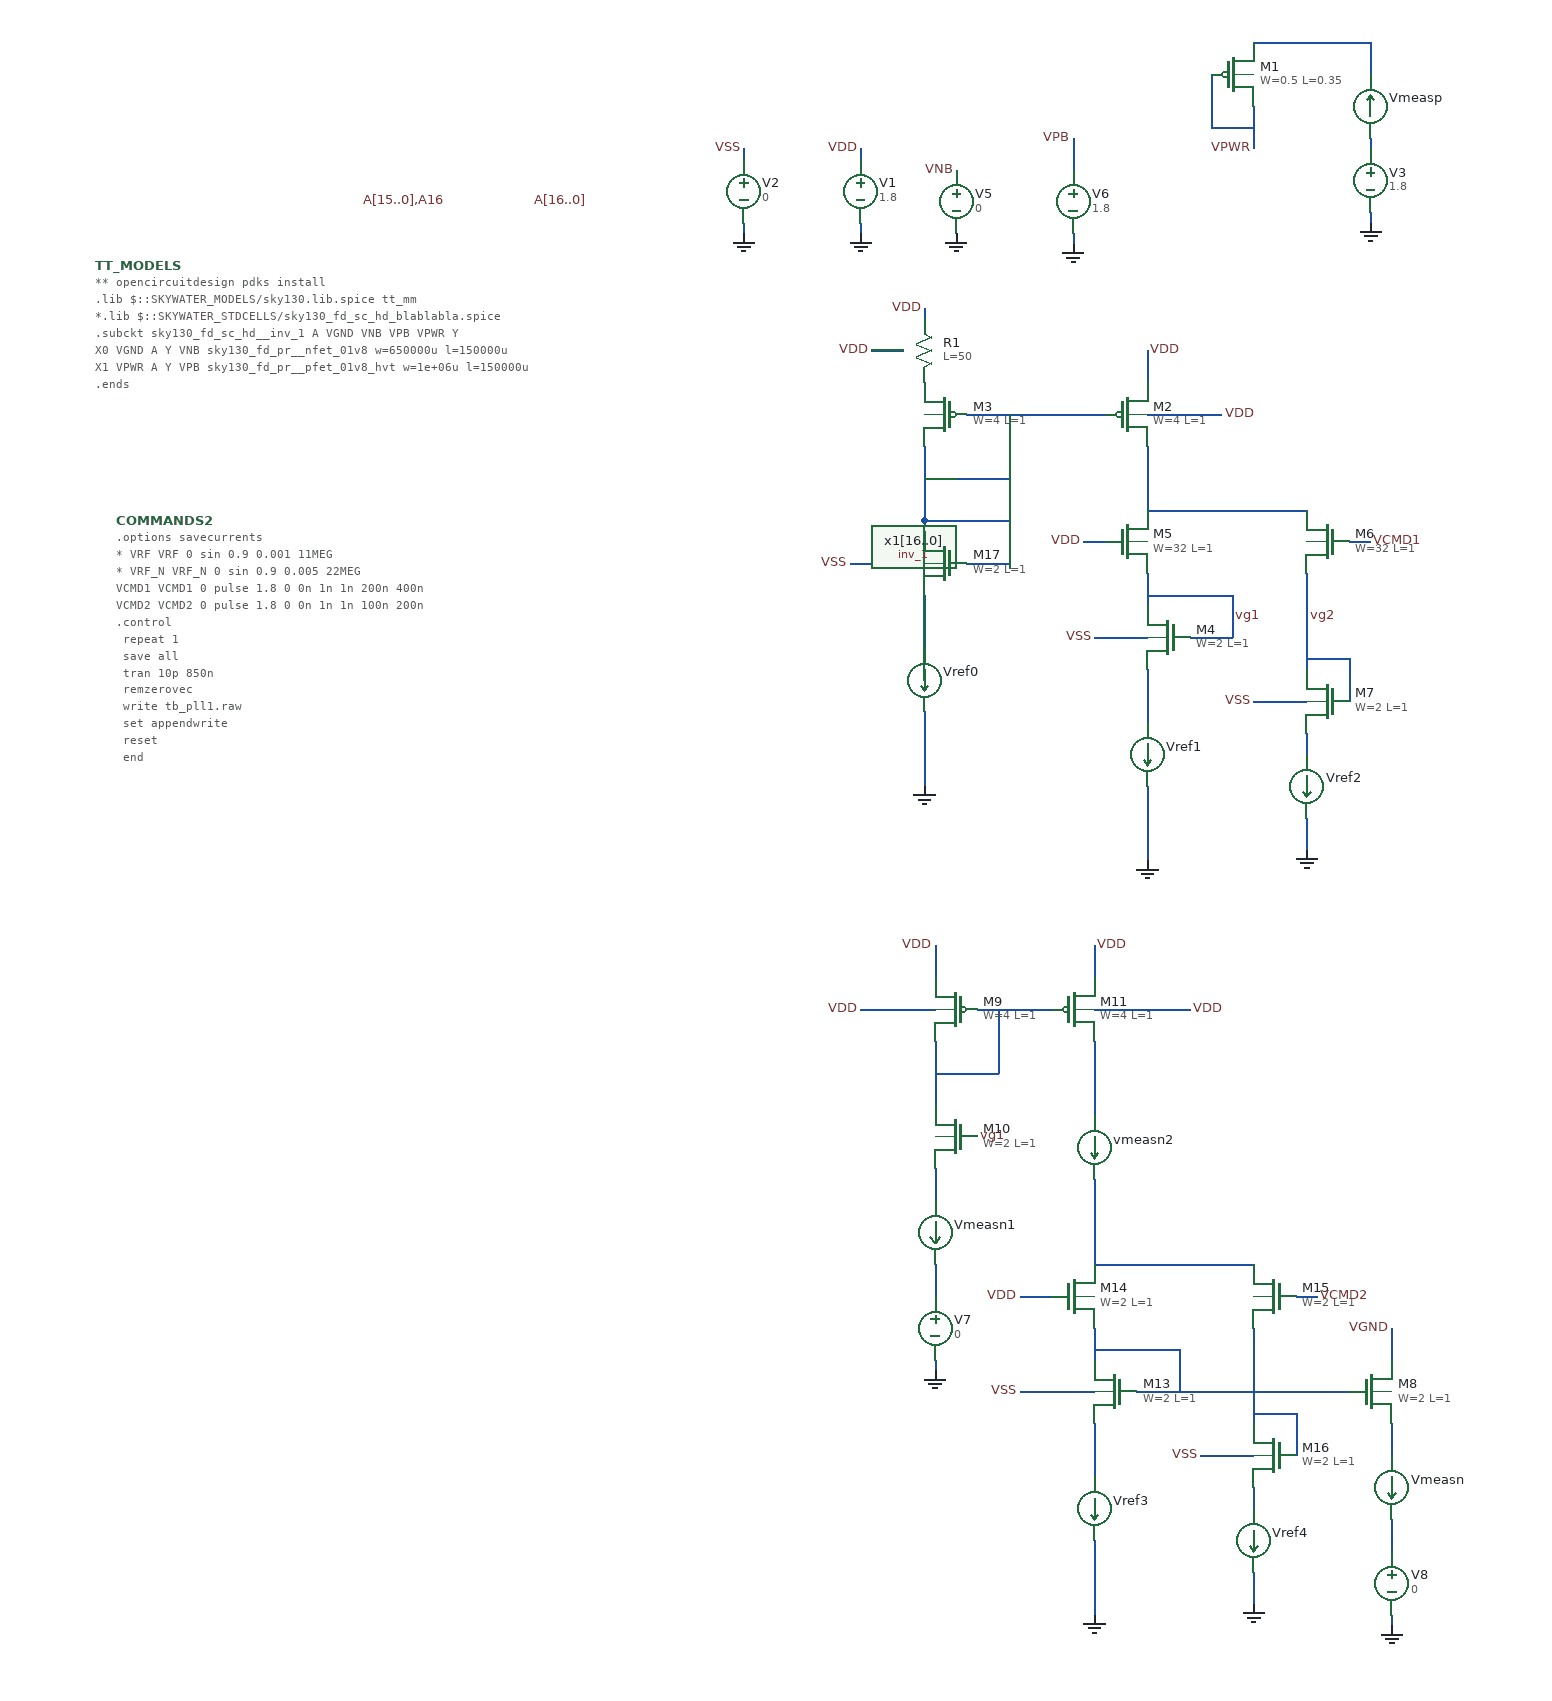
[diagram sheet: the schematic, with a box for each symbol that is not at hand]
v {xschem version=3.4.4 file_version=1.2
}
G {}
K {}
V {}
S {}
E {}
B 2 2330 -870 3130 -470 {flags=graph
y1=-3e-06
y2=4.9e-05
ypos1=0
ypos2=2
divy=5
subdivy=1
unity=1
x1=2.57436e-07
x2=5.3519e-07
divx=5
subdivx=1
xlabmag=1.0
ylabmag=1.0


dataset=0
unitx=1
logx=0
logy=0


color="5 4"
node="i(vref3)
i(vref4)"}
B 2 2330 -470 3130 -70 {flags=graph
y1=-0.263991
y2=1.56078
ypos1=0
ypos2=2
divy=5
subdivy=1
unity=1
x1=2.57436e-07
x2=5.3519e-07
divx=5
subdivx=1
xlabmag=1.0
ylabmag=1.0


dataset=0
unitx=1
logx=0
logy=0





color="4 7 8"
node="a16
a15
a14"}
B 2 2330 -1270 3130 -870 {flags=graph
y1=-4.4e-06
y2=0.00012
ypos1=0
ypos2=2
divy=5
subdivy=1
unity=1
x1=2.57436e-07
x2=5.3519e-07
divx=5
subdivx=1
xlabmag=1.0
ylabmag=1.0


dataset=0
unitx=1
logx=0
logy=0


color="5 4"
node="i(vref1)
i(vref2)"}
B 2 2330 -1670 3130 -1270 {flags=graph
y1=0
y2=3
ypos1=0
ypos2=2
divy=5
subdivy=1
unity=1
x1=2.57436e-07
x2=5.3519e-07
divx=5
subdivx=1
xlabmag=1.0
ylabmag=1.0


dataset=0
unitx=1
logx=0
logy=0



color="6 4"
node="\\"VCMD1 1.8 / 2 +\\"
\\"VCMD2 1.8 /\\""}
N 1740 -1480 1740 -1470 {
lab=VPB}
N 1740 -1410 1740 -1400 {
lab=GND}
N 1740 -1500 1740 -1480 {
lab=VPB}
N 2020 -1500 2020 -1490 {
lab=#net1}
N 2020 -1430 2020 -1420 {
lab=GND}
N 1910 -1530 1910 -1490 {
lab=VPWR}
N 1910 -1590 2020 -1590 {
lab=#net2}
N 2020 -1590 2020 -1560 {
lab=#net2}
N 1870 -1560 1870 -1510 {
lab=VPWR}
N 1870 -1510 1910 -1510 {
lab=VPWR}
N 1430 -1490 1430 -1480 {
lab=VSS}
N 1540 -1490 1540 -1480 {
lab=VDD}
N 1430 -1420 1430 -1410 {
lab=GND}
N 1540 -1420 1540 -1410 {
lab=GND}
N 1810 -830 1810 -820 {
lab=GND}
N 1890 -1070 1890 -1030 {
lab=vg1}
N 1810 -1070 1890 -1070 {
lab=vg1}
N 1810 -1000 1810 -950 {
lab=#net3}
N 1810 -1170 1810 -1150 {
lab=#net4}
N 1810 -1090 1810 -1060 {
lab=vg1}
N 1810 -1150 1960 -1150 {
lab=#net4}
N 2000 -1120 2020 -1120 {
lab=VCMD1}
N 1960 -1090 1960 -1000 {
lab=vg2}
N 1910 -970 1960 -970 {
lab=VSS}
N 1810 -930 1810 -920 {
lab=#net5}
N 1810 -890 1810 -830 {
lab=GND}
N 1960 -860 1960 -830 {
lab=GND}
N 1960 -940 1960 -920 {
lab=#net6}
N 2000 -1010 2000 -970 {
lab=vg2}
N 1960 -1010 2000 -1010 {
lab=vg2}
N 1790 -1030 1810 -1030 {
lab=VSS}
N 1610 -510 1610 -500 {
lab=#net7}
N 1610 -350 1610 -340 {
lab=GND}
N 1610 -530 1610 -510 {
lab=#net7}
N 1610 -440 1610 -410 {
lab=#net8}
N 1610 -740 1610 -710 {
lab=VDD}
N 1650 -680 1660 -680 {
lab=#net9}
N 1610 -650 1610 -590 {
lab=#net9}
N 1540 -680 1610 -680 {
lab=VDD}
N 1660 -680 1720 -680 {
lab=#net9}
N 1760 -680 1850 -680 {
lab=VDD}
N 2040 -270 2040 -260 {
lab=#net10}
N 2040 -110 2040 -100 {
lab=GND}
N 2040 -290 2040 -270 {
lab=#net10}
N 2040 -380 2040 -350 {
lab=VGND}
N 2040 -200 2040 -170 {
lab=#net11}
N 1760 -120 1760 -110 {
lab=GND}
N 1800 -320 2000 -320 {
lab=#net12}
N 1840 -360 1840 -320 {
lab=#net12}
N 1760 -360 1840 -360 {
lab=#net12}
N 1760 -290 1760 -240 {
lab=#net13}
N 1690 -410 1720 -410 {
lab=VDD}
N 1760 -380 1760 -350 {
lab=#net12}
N 1760 -440 1910 -440 {
lab=#net14}
N 1950 -410 1970 -410 {
lab=VCMD2}
N 1910 -380 1910 -290 {
lab=#net15}
N 1860 -260 1910 -260 {
lab=VSS}
N 1760 -220 1760 -210 {
lab=#net16}
N 1760 -180 1760 -120 {
lab=GND}
N 1910 -150 1910 -120 {
lab=GND}
N 1910 -230 1910 -210 {
lab=#net17}
N 1950 -300 1950 -260 {
lab=#net15}
N 1910 -300 1950 -300 {
lab=#net15}
N 1740 -320 1760 -320 {
lab=VSS}
N 1690 -320 1740 -320 {
lab=VSS}
N 1850 -1030 1890 -1030 {
lab=vg1}
N 1670 -680 1670 -620 {
lab=#net9}
N 1610 -620 1670 -620 {
lab=#net9}
N 1760 -740 1760 -710 {
lab=VDD}
N 1600 -1340 1600 -1330 {
lab=VDD}
N 1810 -1300 1810 -1270 {
lab=VDD}
N 1810 -1240 1880 -1240 {
lab=VDD}
N 1550 -1300 1580 -1300 {
lab=VDD}
N 1600 -900 1600 -890 {
lab=GND}
N 1680 -1140 1680 -1100 {
lab=#net18}
N 1600 -1140 1680 -1140 {
lab=#net18}
N 1600 -1070 1600 -1020 {
lab=#net19}
N 1600 -1000 1600 -990 {
lab=#net20}
N 1600 -960 1600 -900 {
lab=GND}
N 1580 -1100 1600 -1100 {
lab=VSS}
N 1530 -1100 1580 -1100 {
lab=VSS}
N 1640 -1100 1680 -1100 {
lab=#net18}
N 1760 -1030 1790 -1030 {
lab=VSS}
N 1750 -1120 1770 -1120 {
lab=VDD}
N 1600 -1140 1600 -1130 {
lab=#net18}
N 1640 -1240 1770 -1240 {
lab=#net18}
N 1810 -1210 1810 -1170 {
lab=#net4}
N 1600 -1210 1600 -1140 {
lab=#net18}
N 1680 -1240 1680 -1180 {
lab=#net18}
N 1600 -1180 1680 -1180 {
lab=#net18}
N 1760 -650 1760 -580 {
lab=#net21}
N 1760 -520 1760 -440 {
lab=#net14}
C {devices/code.sym} 820 -1380 0 0 {name=TT_MODELS
only_toplevel=true
format="tcleval( @value )"
value="
** opencircuitdesign pdks install
.lib $::SKYWATER_MODELS/sky130.lib.spice tt_mm
*.lib $::SKYWATER_STDCELLS/sky130_fd_sc_hd_blablabla.spice
                                                                                      
.subckt sky130_fd_sc_hd__inv_1 A VGND VNB VPB VPWR Y                                                                
X0 VGND A Y VNB sky130_fd_pr__nfet_01v8 w=650000u l=150000u                                                         
X1 VPWR A Y VPB sky130_fd_pr__pfet_01v8_hvt w=1e+06u l=150000u                                                      
.ends

"
spice_ignore=false}
C {devices/launcher.sym} 2220 -980 0 0 {name=h17 
descr="Load waves" 
tclcommand="
xschem raw_read $netlist_dir/[file tail [file rootname [xschem get current_name]]].raw tran

"
}
C {devices/simulator_commands_shown.sym} 840 -1140 0 0 {name=COMMANDS2
simulator=ngspice
only_toplevel=false 
value="
.options savecurrents
* VRF VRF 0 sin 0.9 0.001 11MEG
* VRF_N VRF_N 0 sin 0.9 0.005 22MEG
VCMD1 VCMD1 0 pulse 1.8 0 0n 1n 1n 200n 400n
VCMD2 VCMD2 0 pulse 1.8 0 0n 1n 1n 100n 200n
.control
  repeat 1
    save all
    tran 10p 850n
    remzerovec
    write tb_pll1.raw
    set appendwrite
    reset
    end
.endc
"}
C {sky130_stdcells/inv_1.sym} 1190 -1440 0 0 {name=x1[16..0] VGND=VGND VNB=VNB VPB=VPB VPWR=VPWR prefix=sky130_fd_sc_hd__ }
C {devices/lab_pin.sym} 1230 -1440 0 1 {name=p1 sig_type=std_logic lab=A[16..0]}
C {devices/lab_pin.sym} 1150 -1440 0 0 {name=p3 sig_type=std_logic lab=A[15..0],A16}
C {devices/vsource.sym} 1630 -1440 0 0 {name=V5 value=0 savecurrent=false}
C {devices/gnd.sym} 1630 -1410 0 0 {name=l5 lab=GND}
C {devices/lab_pin.sym} 1630 -1470 2 1 {name=p6 sig_type=std_logic lab=VNB

}
C {devices/vsource.sym} 1740 -1440 0 0 {name=V6 value=1.8 savecurrent=false}
C {devices/gnd.sym} 1740 -1400 0 0 {name=l6 lab=GND}
C {devices/lab_pin.sym} 1740 -1500 2 1 {name=p14 sig_type=std_logic lab=VPB

}
C {devices/vsource.sym} 2020 -1460 0 0 {name=V3 value=1.8 savecurrent=false}
C {devices/gnd.sym} 2020 -1420 0 0 {name=l1 lab=GND}
C {sky130_fd_pr/pfet_01v8_lvt.sym} 1890 -1560 0 0 {name=M1
W=0.5
L=0.35
nf=1
mult=1
ad="'int((nf+1)/2) * W/nf * 0.29'" 
pd="'2*int((nf+1)/2) * (W/nf + 0.29)'"
as="'int((nf+2)/2) * W/nf * 0.29'" 
ps="'2*int((nf+2)/2) * (W/nf + 0.29)'"
nrd="'0.29 / W'" nrs="'0.29 / W'"
sa=0 sb=0 sd=0
model=pfet_01v8_lvt
spiceprefix=X
}
C {devices/lab_pin.sym} 1910 -1490 2 1 {name=p4 sig_type=std_logic lab=VPWR
}
C {devices/vsource.sym} 1540 -1450 0 0 {name=V1 value=1.8 savecurrent=false}
C {devices/gnd.sym} 1540 -1410 0 0 {name=l2 lab=GND}
C {devices/lab_pin.sym} 1540 -1490 2 1 {name=p19 sig_type=std_logic lab=VDD
}
C {devices/vsource.sym} 1430 -1450 0 0 {name=V2 value=0 savecurrent=false}
C {devices/gnd.sym} 1430 -1410 0 0 {name=l3 lab=GND}
C {devices/lab_pin.sym} 1430 -1490 2 1 {name=p28 sig_type=std_logic lab=VSS
}
C {devices/ammeter.sym} 2020 -1530 2 0 {name=Vmeasp savecurrent=true}
C {devices/gnd.sym} 1810 -820 0 0 {name=l7 lab=GND}
C {devices/gnd.sym} 1630 -1410 0 0 {name=l8 lab=GND}
C {devices/ammeter.sym} 1810 -920 0 0 {name=Vref1 savecurrent=true}
C {sky130_fd_pr/nfet_01v8_lvt.sym} 1830 -1030 0 1 {name=M4
W=2
L=1
nf=1
mult=1
ad="'int((nf+1)/2) * W/nf * 0.29'" 
pd="'2*int((nf+1)/2) * (W/nf + 0.29)'"
as="'int((nf+2)/2) * W/nf * 0.29'" 
ps="'2*int((nf+2)/2) * (W/nf + 0.29)'"
nrd="'0.29 / W'" nrs="'0.29 / W'"
sa=0 sb=0 sd=0
model=nfet_01v8_lvt
spiceprefix=X
}
C {sky130_fd_pr/nfet_01v8_lvt.sym} 1790 -1120 0 0 {name=M5
W=32
L=1
nf=1
mult=1
ad="'int((nf+1)/2) * W/nf * 0.29'" 
pd="'2*int((nf+1)/2) * (W/nf + 0.29)'"
as="'int((nf+2)/2) * W/nf * 0.29'" 
ps="'2*int((nf+2)/2) * (W/nf + 0.29)'"
nrd="'0.29 / W'" nrs="'0.29 / W'"
sa=0 sb=0 sd=0
model=nfet_01v8_lvt
spiceprefix=X
}
C {devices/lab_pin.sym} 1750 -1120 2 1 {name=p8 sig_type=std_logic lab=VDD
}
C {sky130_fd_pr/nfet_01v8_lvt.sym} 1980 -1120 0 1 {name=M6
W=32
L=1
nf=1
mult=1
ad="'int((nf+1)/2) * W/nf * 0.29'" 
pd="'2*int((nf+1)/2) * (W/nf + 0.29)'"
as="'int((nf+2)/2) * W/nf * 0.29'" 
ps="'2*int((nf+2)/2) * (W/nf + 0.29)'"
nrd="'0.29 / W'" nrs="'0.29 / W'"
sa=0 sb=0 sd=0
model=nfet_01v8_lvt
spiceprefix=X
}
C {devices/lab_pin.sym} 2020 -1120 2 0 {name=p9 sig_type=std_logic lab=VCMD1
}
C {sky130_fd_pr/nfet_01v8_lvt.sym} 1980 -970 0 1 {name=M7
W=2
L=1
nf=1
mult=1
ad="'int((nf+1)/2) * W/nf * 0.29'" 
pd="'2*int((nf+1)/2) * (W/nf + 0.29)'"
as="'int((nf+2)/2) * W/nf * 0.29'" 
ps="'2*int((nf+2)/2) * (W/nf + 0.29)'"
nrd="'0.29 / W'" nrs="'0.29 / W'"
sa=0 sb=0 sd=0
model=nfet_01v8_lvt
spiceprefix=X
}
C {devices/lab_pin.sym} 1910 -970 2 1 {name=p10 sig_type=std_logic lab=VSS
}
C {devices/gnd.sym} 1960 -830 0 0 {name=l9 lab=GND}
C {devices/ammeter.sym} 1960 -890 0 0 {name=Vref2 savecurrent=true}
C {devices/lab_pin.sym} 1960 -1050 2 0 {name=p11 sig_type=std_logic lab=vg2
}
C {devices/lab_pin.sym} 1890 -1050 2 0 {name=p12 sig_type=std_logic lab=vg1
}
C {devices/lab_pin.sym} 1760 -1030 2 1 {name=p13 sig_type=std_logic lab=VSS
}
C {devices/vsource.sym} 1610 -380 0 1 {name=V7 value=0 savecurrent=false}
C {devices/gnd.sym} 1610 -340 0 1 {name=l10 lab=GND}
C {devices/ammeter.sym} 1610 -470 0 1 {name=Vmeasn1 savecurrent=true}
C {sky130_fd_pr/nfet_01v8_lvt.sym} 1630 -560 0 1 {name=M10
W=2
L=1
nf=1
mult=1
ad="'int((nf+1)/2) * W/nf * 0.29'" 
pd="'2*int((nf+1)/2) * (W/nf + 0.29)'"
as="'int((nf+2)/2) * W/nf * 0.29'" 
ps="'2*int((nf+2)/2) * (W/nf + 0.29)'"
nrd="'0.29 / W'" nrs="'0.29 / W'"
sa=0 sb=0 sd=0
model=nfet_01v8_lvt
spiceprefix=X
}
C {sky130_fd_pr/pfet_01v8_lvt.sym} 1630 -680 0 1 {name=M9
W=4
L=1
nf=1
mult=1
ad="'int((nf+1)/2) * W/nf * 0.29'" 
pd="'2*int((nf+1)/2) * (W/nf + 0.29)'"
as="'int((nf+2)/2) * W/nf * 0.29'" 
ps="'2*int((nf+2)/2) * (W/nf + 0.29)'"
nrd="'0.29 / W'" nrs="'0.29 / W'"
sa=0 sb=0 sd=0
model=pfet_01v8_lvt
spiceprefix=X
}
C {devices/lab_pin.sym} 1610 -740 2 1 {name=p15 sig_type=std_logic lab=VDD
}
C {sky130_fd_pr/pfet_01v8_lvt.sym} 1740 -680 0 0 {name=M11
W=4
L=1
nf=1
mult=1
ad="'int((nf+1)/2) * W/nf * 0.29'" 
pd="'2*int((nf+1)/2) * (W/nf + 0.29)'"
as="'int((nf+2)/2) * W/nf * 0.29'" 
ps="'2*int((nf+2)/2) * (W/nf + 0.29)'"
nrd="'0.29 / W'" nrs="'0.29 / W'"
sa=0 sb=0 sd=0
model=pfet_01v8_lvt
spiceprefix=X
}
C {devices/lab_pin.sym} 1540 -680 2 1 {name=p16 sig_type=std_logic lab=VDD
}
C {devices/lab_pin.sym} 1850 -680 2 0 {name=p17 sig_type=std_logic lab=VDD
}
C {devices/lab_pin.sym} 1650 -560 2 0 {name=p18 sig_type=std_logic lab=vg1
}
C {devices/vsource.sym} 2040 -140 0 0 {name=V8 value=0 savecurrent=false}
C {devices/gnd.sym} 2040 -100 0 0 {name=l11 lab=GND}
C {sky130_fd_pr/nfet_01v8_lvt.sym} 2020 -320 0 0 {name=M8
W=2
L=1
nf=1
mult=1
ad="'int((nf+1)/2) * W/nf * 0.29'" 
pd="'2*int((nf+1)/2) * (W/nf + 0.29)'"
as="'int((nf+2)/2) * W/nf * 0.29'" 
ps="'2*int((nf+2)/2) * (W/nf + 0.29)'"
nrd="'0.29 / W'" nrs="'0.29 / W'"
sa=0 sb=0 sd=0
model=nfet_01v8_lvt
spiceprefix=X
}
C {devices/lab_pin.sym} 2040 -380 2 1 {name=p20 sig_type=std_logic lab=VGND
}
C {devices/ammeter.sym} 2040 -230 0 0 {name=Vmeasn savecurrent=true}
C {devices/gnd.sym} 1760 -110 0 0 {name=l12 lab=GND}
C {devices/ammeter.sym} 1760 -210 0 0 {name=Vref3 savecurrent=true}
C {sky130_fd_pr/nfet_01v8_lvt.sym} 1780 -320 0 1 {name=M13
W=2
L=1
nf=1
mult=1
ad="'int((nf+1)/2) * W/nf * 0.29'" 
pd="'2*int((nf+1)/2) * (W/nf + 0.29)'"
as="'int((nf+2)/2) * W/nf * 0.29'" 
ps="'2*int((nf+2)/2) * (W/nf + 0.29)'"
nrd="'0.29 / W'" nrs="'0.29 / W'"
sa=0 sb=0 sd=0
model=nfet_01v8_lvt
spiceprefix=X
}
C {sky130_fd_pr/nfet_01v8_lvt.sym} 1740 -410 0 0 {name=M14
W=2
L=1
nf=1
mult=1
ad="'int((nf+1)/2) * W/nf * 0.29'" 
pd="'2*int((nf+1)/2) * (W/nf + 0.29)'"
as="'int((nf+2)/2) * W/nf * 0.29'" 
ps="'2*int((nf+2)/2) * (W/nf + 0.29)'"
nrd="'0.29 / W'" nrs="'0.29 / W'"
sa=0 sb=0 sd=0
model=nfet_01v8_lvt
spiceprefix=X
}
C {devices/lab_pin.sym} 1690 -410 2 1 {name=p22 sig_type=std_logic lab=VDD
}
C {sky130_fd_pr/nfet_01v8_lvt.sym} 1930 -410 0 1 {name=M15
W=2
L=1
nf=1
mult=1
ad="'int((nf+1)/2) * W/nf * 0.29'" 
pd="'2*int((nf+1)/2) * (W/nf + 0.29)'"
as="'int((nf+2)/2) * W/nf * 0.29'" 
ps="'2*int((nf+2)/2) * (W/nf + 0.29)'"
nrd="'0.29 / W'" nrs="'0.29 / W'"
sa=0 sb=0 sd=0
model=nfet_01v8_lvt
spiceprefix=X
}
C {devices/lab_pin.sym} 1970 -410 2 0 {name=p23 sig_type=std_logic lab=VCMD2
}
C {sky130_fd_pr/nfet_01v8_lvt.sym} 1930 -260 0 1 {name=M16
W=2
L=1
nf=1
mult=1
ad="'int((nf+1)/2) * W/nf * 0.29'" 
pd="'2*int((nf+1)/2) * (W/nf + 0.29)'"
as="'int((nf+2)/2) * W/nf * 0.29'" 
ps="'2*int((nf+2)/2) * (W/nf + 0.29)'"
nrd="'0.29 / W'" nrs="'0.29 / W'"
sa=0 sb=0 sd=0
model=nfet_01v8_lvt
spiceprefix=X
}
C {devices/lab_pin.sym} 1860 -260 2 1 {name=p24 sig_type=std_logic lab=VSS
}
C {devices/gnd.sym} 1910 -120 0 0 {name=l13 lab=GND}
C {devices/ammeter.sym} 1910 -180 0 0 {name=Vref4 savecurrent=true}
C {devices/lab_pin.sym} 1690 -320 2 1 {name=p27 sig_type=std_logic lab=VSS
}
C {devices/lab_pin.sym} 1760 -740 2 0 {name=p5 sig_type=std_logic lab=VDD
}
C {devices/lab_pin.sym} 1600 -1340 2 1 {name=p2 sig_type=std_logic lab=VDD
}
C {sky130_fd_pr/res_high_po_0p35.sym} 1600 -1300 0 0 {name=R1
L=50
model=res_high_po_0p35
spiceprefix=X
mult=1}
C {sky130_fd_pr/pfet_01v8_lvt.sym} 1790 -1240 0 0 {name=M2
W=4
L=1
nf=1
mult=1
ad="'int((nf+1)/2) * W/nf * 0.29'" 
pd="'2*int((nf+1)/2) * (W/nf + 0.29)'"
as="'int((nf+2)/2) * W/nf * 0.29'" 
ps="'2*int((nf+2)/2) * (W/nf + 0.29)'"
nrd="'0.29 / W'" nrs="'0.29 / W'"
sa=0 sb=0 sd=0
model=pfet_01v8_lvt
spiceprefix=X
}
C {devices/lab_pin.sym} 1810 -1300 2 0 {name=p25 sig_type=std_logic lab=VDD
}
C {devices/lab_pin.sym} 1880 -1240 2 0 {name=p26 sig_type=std_logic lab=VDD
}
C {devices/lab_pin.sym} 1550 -1300 2 1 {name=p29 sig_type=std_logic lab=VDD
}
C {devices/gnd.sym} 1600 -890 0 0 {name=l14 lab=GND}
C {devices/ammeter.sym} 1600 -990 0 0 {name=Vref0 savecurrent=true}
C {sky130_fd_pr/nfet_01v8_lvt.sym} 1620 -1100 0 1 {name=M17
W=2
L=1
nf=1
mult=1
ad="'int((nf+1)/2) * W/nf * 0.29'" 
pd="'2*int((nf+1)/2) * (W/nf + 0.29)'"
as="'int((nf+2)/2) * W/nf * 0.29'" 
ps="'2*int((nf+2)/2) * (W/nf + 0.29)'"
nrd="'0.29 / W'" nrs="'0.29 / W'"
sa=0 sb=0 sd=0
model=nfet_01v8_lvt
spiceprefix=X
}
C {devices/lab_pin.sym} 1530 -1100 2 1 {name=p31 sig_type=std_logic lab=VSS
}
C {sky130_fd_pr/pfet_01v8_lvt.sym} 1620 -1240 0 1 {name=M3
W=4
L=1
nf=1
mult=1
ad="'int((nf+1)/2) * W/nf * 0.29'" 
pd="'2*int((nf+1)/2) * (W/nf + 0.29)'"
as="'int((nf+2)/2) * W/nf * 0.29'" 
ps="'2*int((nf+2)/2) * (W/nf + 0.29)'"
nrd="'0.29 / W'" nrs="'0.29 / W'"
sa=0 sb=0 sd=0
model=pfet_01v8_lvt
spiceprefix=X
}
C {devices/ammeter.sym} 1760 -550 0 0 {name=vmeasn2 savecurrent=true}
